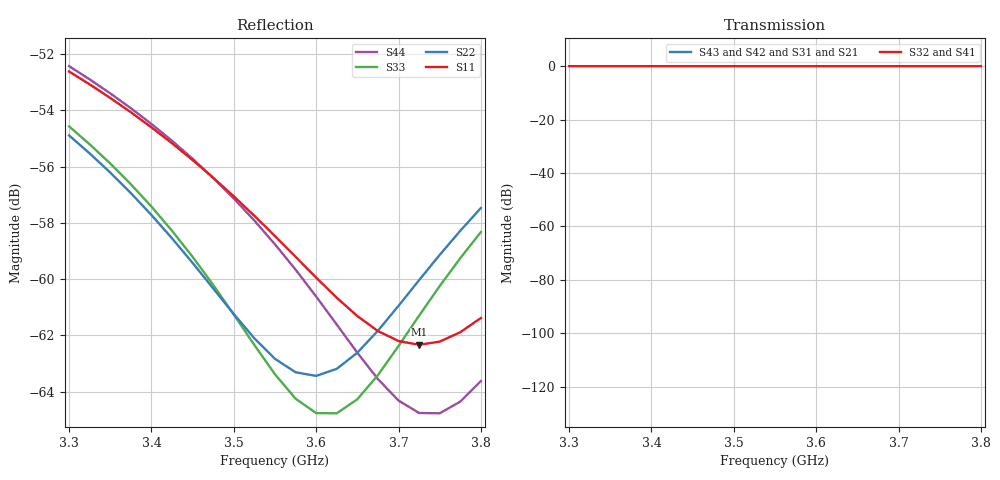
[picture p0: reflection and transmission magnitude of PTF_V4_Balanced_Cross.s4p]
! Touchstone file exported from HFSS 2025.2.4
!  File:  C:/Users/devel/OneDrive/Documents/Velocity-Connect/hfss/Velocity_Connect_PTF_V4_FourPort_Feedthrough.aedt
!  Generated:  12:59:01 PM Aug 25, 2026
!  Design:  VC_PTF_V4_FourPortFeedthrough
!  Project:  Velocity_Connect_PTF_V4_FourPort_Feedthrough
# GHz S RI R 50.000000
! Terminal data exported
! Port[1] = Port1_DonorMinus
! Port[2] = Port2_DonorPlus
! Port[3] = Port3_ServiceMinus
! Port[4] = Port4_ServicePlus
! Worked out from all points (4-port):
!   21 points, 3.3 GHz to 3.8 GHz, reference 50 ohm
!   strongest paths, dB at 3.3 GHz, 3.425 GHz, 3.55 GHz, 3.675 GHz, 3.8 GHz:
!     S32: 0.0, 0.0, 0.0, 0.0, 0.0
!     S41: 0.0, 0.0, 0.0, 0.0, 0.0
!     S43: -, -, -, -, -
!     S42: -, -, -, -, -
!     S31: -, -, -, -, -
!     S21: -, -, -, -, -
!   lowest |S11| = -62.3 dB at 3.725 GHz (marker M1), VSWR 1.00, Z = 50.1 - j0.0238 ohm
!   |S11| at or under -10 dB: start of sweep to end of sweep
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3.3  0.000512 0.00228  0 0  0 0  -0.9895 -0.1273
     0 0  0.00035 0.00177  -0.9895 -0.1275  0 0
     0 0  -0.9895 -0.1275  -0.000949 0.00161  0 0
     -0.9895 -0.1273  0 0  0 0  -0.00124 0.00204
3.425  0.000789 0.00155  0 0  0 0  -0.9976 -0.0138
       0 0  0.000605 0.00102  -0.9976 -0.014  0 0
       0 0  -0.9976 -0.014  -0.000685 0.00101  0 0
       -0.9976 -0.0138  0 0  0 0  -0.000889 0.00152
3.55  0.000887 0.000797  0 0  0 0  -0.9926 0.0999
      0 0  0.000685 0.000228  -0.9926 0.0997  0 0
      0 0  -0.9926 0.0997  -0.000571 0.000365  0 0
      -0.9926 0.0999  0 0  0 0  -0.000664 0.000943
3.6  0.000877 0.000494  0 0  0 0  -0.987 0.1451
     0 0  0.000667 -8.92e-05  -0.987 0.1449  0 0
     0 0  -0.987 0.1449  -0.000569 0.000103  0 0
     -0.987 0.1451  0 0  0 0  -0.00061 0.000704
3.65  0.000837 0.000196  0 0  0 0  -0.9793 0.19
      0 0  0.000621 -0.000403  -0.9794 0.1898  0 0
      0 0  -0.9794 0.1898  -0.000591 -0.000157  0 0
      -0.9793 0.19  0 0  0 0  -0.000578 0.000462
3.725  0.000727 -0.000238  0 0  0 0  -0.964 0.2565
       0 0  0.000499 -0.000862  -0.9641 0.2563  0 0
       0 0  -0.9641 0.2563  -0.000671 -0.00054  0 0
       -0.964 0.2565  0 0  0 0  -0.00057 9.99e-05
3.8  0.000557 -0.000646  0 0  0 0  -0.9442 0.3219
     0 0  0.000316 -0.0013  -0.9442 0.3217  0 0
     0 0  -0.9442 0.3217  -0.000804 -0.000907  0 0
     -0.9442 0.3219  0 0  0 0  -0.000608 -0.000256
